# Generated deterministically by seda-macro-lef-normalizer-v1; recipe orfs-asap7-fakeram-m4-v1.
VERSION 5.8 ;
BUSBITCHARS "[]" ;
DIVIDERCHAR "/" ;

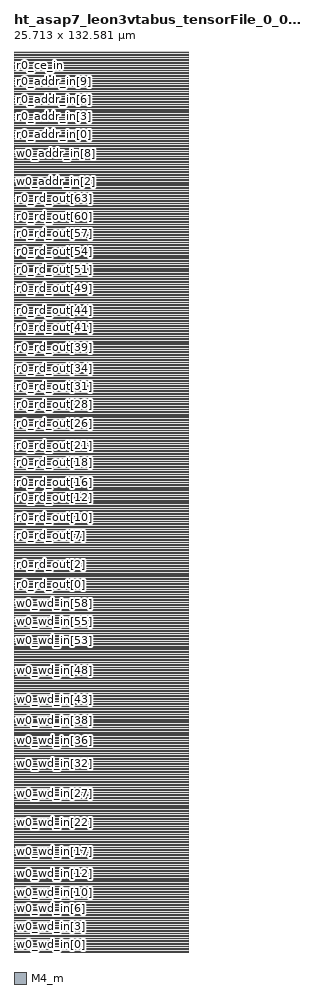
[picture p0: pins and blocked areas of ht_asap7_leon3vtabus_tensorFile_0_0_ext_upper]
MACRO ht_asap7_leon3vtabus_tensorFile_0_0_ext_upper
  FOREIGN ht_asap7_leon3vtabus_tensorFile_0_0_ext_upper 0 0 ;
  CLASS BLOCK ;
  ORIGIN 0 0 ;
  SIZE 25.713 BY 132.581 ;
  SYMMETRY X Y R90 ;
  PIN w0_wd_in[0]
    DIRECTION INPUT ;
    USE SIGNAL ;
    SHAPE ABUTMENT ;
    PORT
      LAYER M4_m ;
      RECT 0 0.048 0.024 0.072 ;
    END
  END w0_wd_in[0]
  PIN w0_wd_in[1]
    DIRECTION INPUT ;
    USE SIGNAL ;
    SHAPE ABUTMENT ;
    PORT
      LAYER M4_m ;
      RECT 0 0.912 0.024 0.936 ;
    END
  END w0_wd_in[1]
  PIN w0_wd_in[2]
    DIRECTION INPUT ;
    USE SIGNAL ;
    SHAPE ABUTMENT ;
    PORT
      LAYER M4_m ;
      RECT 0 1.776 0.024 1.8 ;
    END
  END w0_wd_in[2]
  PIN w0_wd_in[3]
    DIRECTION INPUT ;
    USE SIGNAL ;
    SHAPE ABUTMENT ;
    PORT
      LAYER M4_m ;
      RECT 0 2.64 0.024 2.664 ;
    END
  END w0_wd_in[3]
  PIN w0_wd_in[4]
    DIRECTION INPUT ;
    USE SIGNAL ;
    SHAPE ABUTMENT ;
    PORT
      LAYER M4_m ;
      RECT 0 3.504 0.024 3.528 ;
    END
  END w0_wd_in[4]
  PIN w0_wd_in[5]
    DIRECTION INPUT ;
    USE SIGNAL ;
    SHAPE ABUTMENT ;
    PORT
      LAYER M4_m ;
      RECT 0 4.368 0.024 4.392 ;
    END
  END w0_wd_in[5]
  PIN w0_wd_in[6]
    DIRECTION INPUT ;
    USE SIGNAL ;
    SHAPE ABUTMENT ;
    PORT
      LAYER M4_m ;
      RECT 0 5.232 0.024 5.256 ;
    END
  END w0_wd_in[6]
  PIN w0_wd_in[7]
    DIRECTION INPUT ;
    USE SIGNAL ;
    SHAPE ABUTMENT ;
    PORT
      LAYER M4_m ;
      RECT 0 6.096 0.024 6.12 ;
    END
  END w0_wd_in[7]
  PIN w0_wd_in[8]
    DIRECTION INPUT ;
    USE SIGNAL ;
    SHAPE ABUTMENT ;
    PORT
      LAYER M4_m ;
      RECT 0 6.96 0.024 6.984 ;
    END
  END w0_wd_in[8]
  PIN w0_wd_in[9]
    DIRECTION INPUT ;
    USE SIGNAL ;
    SHAPE ABUTMENT ;
    PORT
      LAYER M4_m ;
      RECT 0 7.824 0.024 7.848 ;
    END
  END w0_wd_in[9]
  PIN w0_wd_in[10]
    DIRECTION INPUT ;
    USE SIGNAL ;
    SHAPE ABUTMENT ;
    PORT
      LAYER M4_m ;
      RECT 0 8.688 0.024 8.712 ;
    END
  END w0_wd_in[10]
  PIN w0_wd_in[11]
    DIRECTION INPUT ;
    USE SIGNAL ;
    SHAPE ABUTMENT ;
    PORT
      LAYER M4_m ;
      RECT 0 9.552 0.024 9.576 ;
    END
  END w0_wd_in[11]
  PIN w0_wd_in[12]
    DIRECTION INPUT ;
    USE SIGNAL ;
    SHAPE ABUTMENT ;
    PORT
      LAYER M4_m ;
      RECT 0 10.416 0.024 10.44 ;
    END
  END w0_wd_in[12]
  PIN w0_wd_in[13]
    DIRECTION INPUT ;
    USE SIGNAL ;
    SHAPE ABUTMENT ;
    PORT
      LAYER M4_m ;
      RECT 0 11.28 0.024 11.304 ;
    END
  END w0_wd_in[13]
  PIN w0_wd_in[14]
    DIRECTION INPUT ;
    USE SIGNAL ;
    SHAPE ABUTMENT ;
    PORT
      LAYER M4_m ;
      RECT 0 12.144 0.024 12.168 ;
    END
  END w0_wd_in[14]
  PIN w0_wd_in[15]
    DIRECTION INPUT ;
    USE SIGNAL ;
    SHAPE ABUTMENT ;
    PORT
      LAYER M4_m ;
      RECT 0 13.008 0.024 13.032 ;
    END
  END w0_wd_in[15]
  PIN w0_wd_in[16]
    DIRECTION INPUT ;
    USE SIGNAL ;
    SHAPE ABUTMENT ;
    PORT
      LAYER M4_m ;
      RECT 0 13.872 0.024 13.896 ;
    END
  END w0_wd_in[16]
  PIN w0_wd_in[17]
    DIRECTION INPUT ;
    USE SIGNAL ;
    SHAPE ABUTMENT ;
    PORT
      LAYER M4_m ;
      RECT 0 14.736 0.024 14.76 ;
    END
  END w0_wd_in[17]
  PIN w0_wd_in[18]
    DIRECTION INPUT ;
    USE SIGNAL ;
    SHAPE ABUTMENT ;
    PORT
      LAYER M4_m ;
      RECT 0 15.6 0.024 15.624 ;
    END
  END w0_wd_in[18]
  PIN w0_wd_in[19]
    DIRECTION INPUT ;
    USE SIGNAL ;
    SHAPE ABUTMENT ;
    PORT
      LAYER M4_m ;
      RECT 0 16.464 0.024 16.488 ;
    END
  END w0_wd_in[19]
  PIN w0_wd_in[20]
    DIRECTION INPUT ;
    USE SIGNAL ;
    SHAPE ABUTMENT ;
    PORT
      LAYER M4_m ;
      RECT 0 17.328 0.024 17.352 ;
    END
  END w0_wd_in[20]
  PIN w0_wd_in[21]
    DIRECTION INPUT ;
    USE SIGNAL ;
    SHAPE ABUTMENT ;
    PORT
      LAYER M4_m ;
      RECT 0 18.192 0.024 18.216 ;
    END
  END w0_wd_in[21]
  PIN w0_wd_in[22]
    DIRECTION INPUT ;
    USE SIGNAL ;
    SHAPE ABUTMENT ;
    PORT
      LAYER M4_m ;
      RECT 0 19.056 0.024 19.08 ;
    END
  END w0_wd_in[22]
  PIN w0_wd_in[23]
    DIRECTION INPUT ;
    USE SIGNAL ;
    SHAPE ABUTMENT ;
    PORT
      LAYER M4_m ;
      RECT 0 19.92 0.024 19.944 ;
    END
  END w0_wd_in[23]
  PIN w0_wd_in[24]
    DIRECTION INPUT ;
    USE SIGNAL ;
    SHAPE ABUTMENT ;
    PORT
      LAYER M4_m ;
      RECT 0 20.784 0.024 20.808 ;
    END
  END w0_wd_in[24]
  PIN w0_wd_in[25]
    DIRECTION INPUT ;
    USE SIGNAL ;
    SHAPE ABUTMENT ;
    PORT
      LAYER M4_m ;
      RECT 0 21.648 0.024 21.672 ;
    END
  END w0_wd_in[25]
  PIN w0_wd_in[26]
    DIRECTION INPUT ;
    USE SIGNAL ;
    SHAPE ABUTMENT ;
    PORT
      LAYER M4_m ;
      RECT 0 22.512 0.024 22.536 ;
    END
  END w0_wd_in[26]
  PIN w0_wd_in[27]
    DIRECTION INPUT ;
    USE SIGNAL ;
    SHAPE ABUTMENT ;
    PORT
      LAYER M4_m ;
      RECT 0 23.376 0.024 23.4 ;
    END
  END w0_wd_in[27]
  PIN w0_wd_in[28]
    DIRECTION INPUT ;
    USE SIGNAL ;
    SHAPE ABUTMENT ;
    PORT
      LAYER M4_m ;
      RECT 0 24.24 0.024 24.264 ;
    END
  END w0_wd_in[28]
  PIN w0_wd_in[29]
    DIRECTION INPUT ;
    USE SIGNAL ;
    SHAPE ABUTMENT ;
    PORT
      LAYER M4_m ;
      RECT 0 25.104 0.024 25.128 ;
    END
  END w0_wd_in[29]
  PIN w0_wd_in[30]
    DIRECTION INPUT ;
    USE SIGNAL ;
    SHAPE ABUTMENT ;
    PORT
      LAYER M4_m ;
      RECT 0 25.968 0.024 25.992 ;
    END
  END w0_wd_in[30]
  PIN w0_wd_in[31]
    DIRECTION INPUT ;
    USE SIGNAL ;
    SHAPE ABUTMENT ;
    PORT
      LAYER M4_m ;
      RECT 0 26.832 0.024 26.856 ;
    END
  END w0_wd_in[31]
  PIN w0_wd_in[32]
    DIRECTION INPUT ;
    USE SIGNAL ;
    SHAPE ABUTMENT ;
    PORT
      LAYER M4_m ;
      RECT 0 27.696 0.024 27.72 ;
    END
  END w0_wd_in[32]
  PIN w0_wd_in[33]
    DIRECTION INPUT ;
    USE SIGNAL ;
    SHAPE ABUTMENT ;
    PORT
      LAYER M4_m ;
      RECT 0 28.56 0.024 28.584 ;
    END
  END w0_wd_in[33]
  PIN w0_wd_in[34]
    DIRECTION INPUT ;
    USE SIGNAL ;
    SHAPE ABUTMENT ;
    PORT
      LAYER M4_m ;
      RECT 0 29.424 0.024 29.448 ;
    END
  END w0_wd_in[34]
  PIN w0_wd_in[35]
    DIRECTION INPUT ;
    USE SIGNAL ;
    SHAPE ABUTMENT ;
    PORT
      LAYER M4_m ;
      RECT 0 30.288 0.024 30.312 ;
    END
  END w0_wd_in[35]
  PIN w0_wd_in[36]
    DIRECTION INPUT ;
    USE SIGNAL ;
    SHAPE ABUTMENT ;
    PORT
      LAYER M4_m ;
      RECT 0 31.152 0.024 31.176 ;
    END
  END w0_wd_in[36]
  PIN w0_wd_in[37]
    DIRECTION INPUT ;
    USE SIGNAL ;
    SHAPE ABUTMENT ;
    PORT
      LAYER M4_m ;
      RECT 0 32.016 0.024 32.04 ;
    END
  END w0_wd_in[37]
  PIN w0_wd_in[38]
    DIRECTION INPUT ;
    USE SIGNAL ;
    SHAPE ABUTMENT ;
    PORT
      LAYER M4_m ;
      RECT 0 32.88 0.024 32.904 ;
    END
  END w0_wd_in[38]
  PIN w0_wd_in[39]
    DIRECTION INPUT ;
    USE SIGNAL ;
    SHAPE ABUTMENT ;
    PORT
      LAYER M4_m ;
      RECT 0 33.744 0.024 33.768 ;
    END
  END w0_wd_in[39]
  PIN w0_wd_in[40]
    DIRECTION INPUT ;
    USE SIGNAL ;
    SHAPE ABUTMENT ;
    PORT
      LAYER M4_m ;
      RECT 0 34.608 0.024 34.632 ;
    END
  END w0_wd_in[40]
  PIN w0_wd_in[41]
    DIRECTION INPUT ;
    USE SIGNAL ;
    SHAPE ABUTMENT ;
    PORT
      LAYER M4_m ;
      RECT 0 35.472 0.024 35.496 ;
    END
  END w0_wd_in[41]
  PIN w0_wd_in[42]
    DIRECTION INPUT ;
    USE SIGNAL ;
    SHAPE ABUTMENT ;
    PORT
      LAYER M4_m ;
      RECT 0 36.336 0.024 36.36 ;
    END
  END w0_wd_in[42]
  PIN w0_wd_in[43]
    DIRECTION INPUT ;
    USE SIGNAL ;
    SHAPE ABUTMENT ;
    PORT
      LAYER M4_m ;
      RECT 0 37.2 0.024 37.224 ;
    END
  END w0_wd_in[43]
  PIN w0_wd_in[44]
    DIRECTION INPUT ;
    USE SIGNAL ;
    SHAPE ABUTMENT ;
    PORT
      LAYER M4_m ;
      RECT 0 38.064 0.024 38.088 ;
    END
  END w0_wd_in[44]
  PIN w0_wd_in[45]
    DIRECTION INPUT ;
    USE SIGNAL ;
    SHAPE ABUTMENT ;
    PORT
      LAYER M4_m ;
      RECT 0 38.928 0.024 38.952 ;
    END
  END w0_wd_in[45]
  PIN w0_wd_in[46]
    DIRECTION INPUT ;
    USE SIGNAL ;
    SHAPE ABUTMENT ;
    PORT
      LAYER M4_m ;
      RECT 0 39.792 0.024 39.816 ;
    END
  END w0_wd_in[46]
  PIN w0_wd_in[47]
    DIRECTION INPUT ;
    USE SIGNAL ;
    SHAPE ABUTMENT ;
    PORT
      LAYER M4_m ;
      RECT 0 40.656 0.024 40.68 ;
    END
  END w0_wd_in[47]
  PIN w0_wd_in[48]
    DIRECTION INPUT ;
    USE SIGNAL ;
    SHAPE ABUTMENT ;
    PORT
      LAYER M4_m ;
      RECT 0 41.52 0.024 41.544 ;
    END
  END w0_wd_in[48]
  PIN w0_wd_in[49]
    DIRECTION INPUT ;
    USE SIGNAL ;
    SHAPE ABUTMENT ;
    PORT
      LAYER M4_m ;
      RECT 0 42.384 0.024 42.408 ;
    END
  END w0_wd_in[49]
  PIN w0_wd_in[50]
    DIRECTION INPUT ;
    USE SIGNAL ;
    SHAPE ABUTMENT ;
    PORT
      LAYER M4_m ;
      RECT 0 43.248 0.024 43.272 ;
    END
  END w0_wd_in[50]
  PIN w0_wd_in[51]
    DIRECTION INPUT ;
    USE SIGNAL ;
    SHAPE ABUTMENT ;
    PORT
      LAYER M4_m ;
      RECT 0 44.112 0.024 44.136 ;
    END
  END w0_wd_in[51]
  PIN w0_wd_in[52]
    DIRECTION INPUT ;
    USE SIGNAL ;
    SHAPE ABUTMENT ;
    PORT
      LAYER M4_m ;
      RECT 0 44.976 0.024 45 ;
    END
  END w0_wd_in[52]
  PIN w0_wd_in[53]
    DIRECTION INPUT ;
    USE SIGNAL ;
    SHAPE ABUTMENT ;
    PORT
      LAYER M4_m ;
      RECT 0 45.84 0.024 45.864 ;
    END
  END w0_wd_in[53]
  PIN w0_wd_in[54]
    DIRECTION INPUT ;
    USE SIGNAL ;
    SHAPE ABUTMENT ;
    PORT
      LAYER M4_m ;
      RECT 0 46.704 0.024 46.728 ;
    END
  END w0_wd_in[54]
  PIN w0_wd_in[55]
    DIRECTION INPUT ;
    USE SIGNAL ;
    SHAPE ABUTMENT ;
    PORT
      LAYER M4_m ;
      RECT 0 47.568 0.024 47.592 ;
    END
  END w0_wd_in[55]
  PIN w0_wd_in[56]
    DIRECTION INPUT ;
    USE SIGNAL ;
    SHAPE ABUTMENT ;
    PORT
      LAYER M4_m ;
      RECT 0 48.432 0.024 48.456 ;
    END
  END w0_wd_in[56]
  PIN w0_wd_in[57]
    DIRECTION INPUT ;
    USE SIGNAL ;
    SHAPE ABUTMENT ;
    PORT
      LAYER M4_m ;
      RECT 0 49.296 0.024 49.32 ;
    END
  END w0_wd_in[57]
  PIN w0_wd_in[58]
    DIRECTION INPUT ;
    USE SIGNAL ;
    SHAPE ABUTMENT ;
    PORT
      LAYER M4_m ;
      RECT 0 50.16 0.024 50.184 ;
    END
  END w0_wd_in[58]
  PIN w0_wd_in[59]
    DIRECTION INPUT ;
    USE SIGNAL ;
    SHAPE ABUTMENT ;
    PORT
      LAYER M4_m ;
      RECT 0 51.024 0.024 51.048 ;
    END
  END w0_wd_in[59]
  PIN w0_wd_in[60]
    DIRECTION INPUT ;
    USE SIGNAL ;
    SHAPE ABUTMENT ;
    PORT
      LAYER M4_m ;
      RECT 0 51.888 0.024 51.912 ;
    END
  END w0_wd_in[60]
  PIN w0_wd_in[61]
    DIRECTION INPUT ;
    USE SIGNAL ;
    SHAPE ABUTMENT ;
    PORT
      LAYER M4_m ;
      RECT 0 52.752 0.024 52.776 ;
    END
  END w0_wd_in[61]
  PIN w0_wd_in[62]
    DIRECTION INPUT ;
    USE SIGNAL ;
    SHAPE ABUTMENT ;
    PORT
      LAYER M4_m ;
      RECT 0 53.616 0.024 53.64 ;
    END
  END w0_wd_in[62]
  PIN w0_wd_in[63]
    DIRECTION INPUT ;
    USE SIGNAL ;
    SHAPE ABUTMENT ;
    PORT
      LAYER M4_m ;
      RECT 0 54.48 0.024 54.504 ;
    END
  END w0_wd_in[63]
  PIN r0_rd_out[0]
    DIRECTION OUTPUT ;
    USE SIGNAL ;
    SHAPE ABUTMENT ;
    PORT
      LAYER M4_m ;
      RECT 0 55.344 0.024 55.368 ;
    END
  END r0_rd_out[0]
  PIN r0_rd_out[1]
    DIRECTION OUTPUT ;
    USE SIGNAL ;
    SHAPE ABUTMENT ;
    PORT
      LAYER M4_m ;
      RECT 0 56.208 0.024 56.232 ;
    END
  END r0_rd_out[1]
  PIN r0_rd_out[2]
    DIRECTION OUTPUT ;
    USE SIGNAL ;
    SHAPE ABUTMENT ;
    PORT
      LAYER M4_m ;
      RECT 0 57.072 0.024 57.096 ;
    END
  END r0_rd_out[2]
  PIN r0_rd_out[3]
    DIRECTION OUTPUT ;
    USE SIGNAL ;
    SHAPE ABUTMENT ;
    PORT
      LAYER M4_m ;
      RECT 0 57.936 0.024 57.96 ;
    END
  END r0_rd_out[3]
  PIN r0_rd_out[4]
    DIRECTION OUTPUT ;
    USE SIGNAL ;
    SHAPE ABUTMENT ;
    PORT
      LAYER M4_m ;
      RECT 0 58.8 0.024 58.824 ;
    END
  END r0_rd_out[4]
  PIN r0_rd_out[5]
    DIRECTION OUTPUT ;
    USE SIGNAL ;
    SHAPE ABUTMENT ;
    PORT
      LAYER M4_m ;
      RECT 0 59.664 0.024 59.688 ;
    END
  END r0_rd_out[5]
  PIN r0_rd_out[6]
    DIRECTION OUTPUT ;
    USE SIGNAL ;
    SHAPE ABUTMENT ;
    PORT
      LAYER M4_m ;
      RECT 0 60.528 0.024 60.552 ;
    END
  END r0_rd_out[6]
  PIN r0_rd_out[7]
    DIRECTION OUTPUT ;
    USE SIGNAL ;
    SHAPE ABUTMENT ;
    PORT
      LAYER M4_m ;
      RECT 0 61.392 0.024 61.416 ;
    END
  END r0_rd_out[7]
  PIN r0_rd_out[8]
    DIRECTION OUTPUT ;
    USE SIGNAL ;
    SHAPE ABUTMENT ;
    PORT
      LAYER M4_m ;
      RECT 0 62.256 0.024 62.28 ;
    END
  END r0_rd_out[8]
  PIN r0_rd_out[9]
    DIRECTION OUTPUT ;
    USE SIGNAL ;
    SHAPE ABUTMENT ;
    PORT
      LAYER M4_m ;
      RECT 0 63.12 0.024 63.144 ;
    END
  END r0_rd_out[9]
  PIN r0_rd_out[10]
    DIRECTION OUTPUT ;
    USE SIGNAL ;
    SHAPE ABUTMENT ;
    PORT
      LAYER M4_m ;
      RECT 0 63.984 0.024 64.008 ;
    END
  END r0_rd_out[10]
  PIN r0_rd_out[11]
    DIRECTION OUTPUT ;
    USE SIGNAL ;
    SHAPE ABUTMENT ;
    PORT
      LAYER M4_m ;
      RECT 0 64.848 0.024 64.872 ;
    END
  END r0_rd_out[11]
  PIN r0_rd_out[12]
    DIRECTION OUTPUT ;
    USE SIGNAL ;
    SHAPE ABUTMENT ;
    PORT
      LAYER M4_m ;
      RECT 0 65.712 0.024 65.736 ;
    END
  END r0_rd_out[12]
  PIN r0_rd_out[13]
    DIRECTION OUTPUT ;
    USE SIGNAL ;
    SHAPE ABUTMENT ;
    PORT
      LAYER M4_m ;
      RECT 0 66.576 0.024 66.6 ;
    END
  END r0_rd_out[13]
  PIN r0_rd_out[14]
    DIRECTION OUTPUT ;
    USE SIGNAL ;
    SHAPE ABUTMENT ;
    PORT
      LAYER M4_m ;
      RECT 0 67.44 0.024 67.464 ;
    END
  END r0_rd_out[14]
  PIN r0_rd_out[15]
    DIRECTION OUTPUT ;
    USE SIGNAL ;
    SHAPE ABUTMENT ;
    PORT
      LAYER M4_m ;
      RECT 0 68.304 0.024 68.328 ;
    END
  END r0_rd_out[15]
  PIN r0_rd_out[16]
    DIRECTION OUTPUT ;
    USE SIGNAL ;
    SHAPE ABUTMENT ;
    PORT
      LAYER M4_m ;
      RECT 0 69.168 0.024 69.192 ;
    END
  END r0_rd_out[16]
  PIN r0_rd_out[17]
    DIRECTION OUTPUT ;
    USE SIGNAL ;
    SHAPE ABUTMENT ;
    PORT
      LAYER M4_m ;
      RECT 0 70.032 0.024 70.056 ;
    END
  END r0_rd_out[17]
  PIN r0_rd_out[18]
    DIRECTION OUTPUT ;
    USE SIGNAL ;
    SHAPE ABUTMENT ;
    PORT
      LAYER M4_m ;
      RECT 0 70.896 0.024 70.92 ;
    END
  END r0_rd_out[18]
  PIN r0_rd_out[19]
    DIRECTION OUTPUT ;
    USE SIGNAL ;
    SHAPE ABUTMENT ;
    PORT
      LAYER M4_m ;
      RECT 0 71.76 0.024 71.784 ;
    END
  END r0_rd_out[19]
  PIN r0_rd_out[20]
    DIRECTION OUTPUT ;
    USE SIGNAL ;
    SHAPE ABUTMENT ;
    PORT
      LAYER M4_m ;
      RECT 0 72.624 0.024 72.648 ;
    END
  END r0_rd_out[20]
  PIN r0_rd_out[21]
    DIRECTION OUTPUT ;
    USE SIGNAL ;
    SHAPE ABUTMENT ;
    PORT
      LAYER M4_m ;
      RECT 0 73.488 0.024 73.512 ;
    END
  END r0_rd_out[21]
  PIN r0_rd_out[22]
    DIRECTION OUTPUT ;
    USE SIGNAL ;
    SHAPE ABUTMENT ;
    PORT
      LAYER M4_m ;
      RECT 0 74.352 0.024 74.376 ;
    END
  END r0_rd_out[22]
  PIN r0_rd_out[23]
    DIRECTION OUTPUT ;
    USE SIGNAL ;
    SHAPE ABUTMENT ;
    PORT
      LAYER M4_m ;
      RECT 0 75.216 0.024 75.24 ;
    END
  END r0_rd_out[23]
  PIN r0_rd_out[24]
    DIRECTION OUTPUT ;
    USE SIGNAL ;
    SHAPE ABUTMENT ;
    PORT
      LAYER M4_m ;
      RECT 0 76.08 0.024 76.104 ;
    END
  END r0_rd_out[24]
  PIN r0_rd_out[25]
    DIRECTION OUTPUT ;
    USE SIGNAL ;
    SHAPE ABUTMENT ;
    PORT
      LAYER M4_m ;
      RECT 0 76.944 0.024 76.968 ;
    END
  END r0_rd_out[25]
  PIN r0_rd_out[26]
    DIRECTION OUTPUT ;
    USE SIGNAL ;
    SHAPE ABUTMENT ;
    PORT
      LAYER M4_m ;
      RECT 0 77.808 0.024 77.832 ;
    END
  END r0_rd_out[26]
  PIN r0_rd_out[27]
    DIRECTION OUTPUT ;
    USE SIGNAL ;
    SHAPE ABUTMENT ;
    PORT
      LAYER M4_m ;
      RECT 0 78.672 0.024 78.696 ;
    END
  END r0_rd_out[27]
  PIN r0_rd_out[28]
    DIRECTION OUTPUT ;
    USE SIGNAL ;
    SHAPE ABUTMENT ;
    PORT
      LAYER M4_m ;
      RECT 0 79.536 0.024 79.56 ;
    END
  END r0_rd_out[28]
  PIN r0_rd_out[29]
    DIRECTION OUTPUT ;
    USE SIGNAL ;
    SHAPE ABUTMENT ;
    PORT
      LAYER M4_m ;
      RECT 0 80.4 0.024 80.424 ;
    END
  END r0_rd_out[29]
  PIN r0_rd_out[30]
    DIRECTION OUTPUT ;
    USE SIGNAL ;
    SHAPE ABUTMENT ;
    PORT
      LAYER M4_m ;
      RECT 0 81.264 0.024 81.288 ;
    END
  END r0_rd_out[30]
  PIN r0_rd_out[31]
    DIRECTION OUTPUT ;
    USE SIGNAL ;
    SHAPE ABUTMENT ;
    PORT
      LAYER M4_m ;
      RECT 0 82.128 0.024 82.152 ;
    END
  END r0_rd_out[31]
  PIN r0_rd_out[32]
    DIRECTION OUTPUT ;
    USE SIGNAL ;
    SHAPE ABUTMENT ;
    PORT
      LAYER M4_m ;
      RECT 0 82.992 0.024 83.016 ;
    END
  END r0_rd_out[32]
  PIN r0_rd_out[33]
    DIRECTION OUTPUT ;
    USE SIGNAL ;
    SHAPE ABUTMENT ;
    PORT
      LAYER M4_m ;
      RECT 0 83.856 0.024 83.88 ;
    END
  END r0_rd_out[33]
  PIN r0_rd_out[34]
    DIRECTION OUTPUT ;
    USE SIGNAL ;
    SHAPE ABUTMENT ;
    PORT
      LAYER M4_m ;
      RECT 0 84.72 0.024 84.744 ;
    END
  END r0_rd_out[34]
  PIN r0_rd_out[35]
    DIRECTION OUTPUT ;
    USE SIGNAL ;
    SHAPE ABUTMENT ;
    PORT
      LAYER M4_m ;
      RECT 0 85.584 0.024 85.608 ;
    END
  END r0_rd_out[35]
  PIN r0_rd_out[36]
    DIRECTION OUTPUT ;
    USE SIGNAL ;
    SHAPE ABUTMENT ;
    PORT
      LAYER M4_m ;
      RECT 0 86.448 0.024 86.472 ;
    END
  END r0_rd_out[36]
  PIN r0_rd_out[37]
    DIRECTION OUTPUT ;
    USE SIGNAL ;
    SHAPE ABUTMENT ;
    PORT
      LAYER M4_m ;
      RECT 0 87.312 0.024 87.336 ;
    END
  END r0_rd_out[37]
  PIN r0_rd_out[38]
    DIRECTION OUTPUT ;
    USE SIGNAL ;
    SHAPE ABUTMENT ;
    PORT
      LAYER M4_m ;
      RECT 0 88.176 0.024 88.2 ;
    END
  END r0_rd_out[38]
  PIN r0_rd_out[39]
    DIRECTION OUTPUT ;
    USE SIGNAL ;
    SHAPE ABUTMENT ;
    PORT
      LAYER M4_m ;
      RECT 0 89.04 0.024 89.064 ;
    END
  END r0_rd_out[39]
  PIN r0_rd_out[40]
    DIRECTION OUTPUT ;
    USE SIGNAL ;
    SHAPE ABUTMENT ;
    PORT
      LAYER M4_m ;
      RECT 0 89.904 0.024 89.928 ;
    END
  END r0_rd_out[40]
  PIN r0_rd_out[41]
    DIRECTION OUTPUT ;
    USE SIGNAL ;
    SHAPE ABUTMENT ;
    PORT
      LAYER M4_m ;
      RECT 0 90.768 0.024 90.792 ;
    END
  END r0_rd_out[41]
  PIN r0_rd_out[42]
    DIRECTION OUTPUT ;
    USE SIGNAL ;
    SHAPE ABUTMENT ;
    PORT
      LAYER M4_m ;
      RECT 0 91.632 0.024 91.656 ;
    END
  END r0_rd_out[42]
  PIN r0_rd_out[43]
    DIRECTION OUTPUT ;
    USE SIGNAL ;
    SHAPE ABUTMENT ;
    PORT
      LAYER M4_m ;
      RECT 0 92.496 0.024 92.52 ;
    END
  END r0_rd_out[43]
  PIN r0_rd_out[44]
    DIRECTION OUTPUT ;
    USE SIGNAL ;
    SHAPE ABUTMENT ;
    PORT
      LAYER M4_m ;
      RECT 0 93.36 0.024 93.384 ;
    END
  END r0_rd_out[44]
  PIN r0_rd_out[45]
    DIRECTION OUTPUT ;
    USE SIGNAL ;
    SHAPE ABUTMENT ;
    PORT
      LAYER M4_m ;
      RECT 0 94.224 0.024 94.248 ;
    END
  END r0_rd_out[45]
  PIN r0_rd_out[46]
    DIRECTION OUTPUT ;
    USE SIGNAL ;
    SHAPE ABUTMENT ;
    PORT
      LAYER M4_m ;
      RECT 0 95.088 0.024 95.112 ;
    END
  END r0_rd_out[46]
  PIN r0_rd_out[47]
    DIRECTION OUTPUT ;
    USE SIGNAL ;
    SHAPE ABUTMENT ;
    PORT
      LAYER M4_m ;
      RECT 0 95.952 0.024 95.976 ;
    END
  END r0_rd_out[47]
  PIN r0_rd_out[48]
    DIRECTION OUTPUT ;
    USE SIGNAL ;
    SHAPE ABUTMENT ;
    PORT
      LAYER M4_m ;
      RECT 0 96.816 0.024 96.84 ;
    END
  END r0_rd_out[48]
  PIN r0_rd_out[49]
    DIRECTION OUTPUT ;
    USE SIGNAL ;
    SHAPE ABUTMENT ;
    PORT
      LAYER M4_m ;
      RECT 0 97.68 0.024 97.704 ;
    END
  END r0_rd_out[49]
  PIN r0_rd_out[50]
    DIRECTION OUTPUT ;
    USE SIGNAL ;
    SHAPE ABUTMENT ;
    PORT
      LAYER M4_m ;
      RECT 0 98.544 0.024 98.568 ;
    END
  END r0_rd_out[50]
  PIN r0_rd_out[51]
    DIRECTION OUTPUT ;
    USE SIGNAL ;
    SHAPE ABUTMENT ;
    PORT
      LAYER M4_m ;
      RECT 0 99.408 0.024 99.432 ;
    END
  END r0_rd_out[51]
  PIN r0_rd_out[52]
    DIRECTION OUTPUT ;
    USE SIGNAL ;
    SHAPE ABUTMENT ;
    PORT
      LAYER M4_m ;
      RECT 0 100.272 0.024 100.296 ;
    END
  END r0_rd_out[52]
  PIN r0_rd_out[53]
    DIRECTION OUTPUT ;
    USE SIGNAL ;
    SHAPE ABUTMENT ;
    PORT
      LAYER M4_m ;
      RECT 0 101.136 0.024 101.16 ;
    END
  END r0_rd_out[53]
  PIN r0_rd_out[54]
    DIRECTION OUTPUT ;
    USE SIGNAL ;
    SHAPE ABUTMENT ;
    PORT
      LAYER M4_m ;
      RECT 0 102 0.024 102.024 ;
    END
  END r0_rd_out[54]
  PIN r0_rd_out[55]
    DIRECTION OUTPUT ;
    USE SIGNAL ;
    SHAPE ABUTMENT ;
    PORT
      LAYER M4_m ;
      RECT 0 102.864 0.024 102.888 ;
    END
  END r0_rd_out[55]
  PIN r0_rd_out[56]
    DIRECTION OUTPUT ;
    USE SIGNAL ;
    SHAPE ABUTMENT ;
    PORT
      LAYER M4_m ;
      RECT 0 103.728 0.024 103.752 ;
    END
  END r0_rd_out[56]
  PIN r0_rd_out[57]
    DIRECTION OUTPUT ;
    USE SIGNAL ;
    SHAPE ABUTMENT ;
    PORT
      LAYER M4_m ;
      RECT 0 104.592 0.024 104.616 ;
    END
  END r0_rd_out[57]
  PIN r0_rd_out[58]
    DIRECTION OUTPUT ;
    USE SIGNAL ;
    SHAPE ABUTMENT ;
    PORT
      LAYER M4_m ;
      RECT 0 105.456 0.024 105.48 ;
    END
  END r0_rd_out[58]
  PIN r0_rd_out[59]
    DIRECTION OUTPUT ;
    USE SIGNAL ;
    SHAPE ABUTMENT ;
    PORT
      LAYER M4_m ;
      RECT 0 106.32 0.024 106.344 ;
    END
  END r0_rd_out[59]
  PIN r0_rd_out[60]
    DIRECTION OUTPUT ;
    USE SIGNAL ;
    SHAPE ABUTMENT ;
    PORT
      LAYER M4_m ;
      RECT 0 107.184 0.024 107.208 ;
    END
  END r0_rd_out[60]
  PIN r0_rd_out[61]
    DIRECTION OUTPUT ;
    USE SIGNAL ;
    SHAPE ABUTMENT ;
    PORT
      LAYER M4_m ;
      RECT 0 108.048 0.024 108.072 ;
    END
  END r0_rd_out[61]
  PIN r0_rd_out[62]
    DIRECTION OUTPUT ;
    USE SIGNAL ;
    SHAPE ABUTMENT ;
    PORT
      LAYER M4_m ;
      RECT 0 108.912 0.024 108.936 ;
    END
  END r0_rd_out[62]
  PIN r0_rd_out[63]
    DIRECTION OUTPUT ;
    USE SIGNAL ;
    SHAPE ABUTMENT ;
    PORT
      LAYER M4_m ;
      RECT 0 109.776 0.024 109.8 ;
    END
  END r0_rd_out[63]
  PIN w0_addr_in[0]
    DIRECTION INPUT ;
    USE SIGNAL ;
    SHAPE ABUTMENT ;
    PORT
      LAYER M4_m ;
      RECT 0 110.64 0.024 110.664 ;
    END
  END w0_addr_in[0]
  PIN w0_addr_in[1]
    DIRECTION INPUT ;
    USE SIGNAL ;
    SHAPE ABUTMENT ;
    PORT
      LAYER M4_m ;
      RECT 0 111.504 0.024 111.528 ;
    END
  END w0_addr_in[1]
  PIN w0_addr_in[2]
    DIRECTION INPUT ;
    USE SIGNAL ;
    SHAPE ABUTMENT ;
    PORT
      LAYER M4_m ;
      RECT 0 112.368 0.024 112.392 ;
    END
  END w0_addr_in[2]
  PIN w0_addr_in[3]
    DIRECTION INPUT ;
    USE SIGNAL ;
    SHAPE ABUTMENT ;
    PORT
      LAYER M4_m ;
      RECT 0 113.232 0.024 113.256 ;
    END
  END w0_addr_in[3]
  PIN w0_addr_in[4]
    DIRECTION INPUT ;
    USE SIGNAL ;
    SHAPE ABUTMENT ;
    PORT
      LAYER M4_m ;
      RECT 0 114.096 0.024 114.12 ;
    END
  END w0_addr_in[4]
  PIN w0_addr_in[5]
    DIRECTION INPUT ;
    USE SIGNAL ;
    SHAPE ABUTMENT ;
    PORT
      LAYER M4_m ;
      RECT 0 114.96 0.024 114.984 ;
    END
  END w0_addr_in[5]
  PIN w0_addr_in[6]
    DIRECTION INPUT ;
    USE SIGNAL ;
    SHAPE ABUTMENT ;
    PORT
      LAYER M4_m ;
      RECT 0 115.824 0.024 115.848 ;
    END
  END w0_addr_in[6]
  PIN w0_addr_in[7]
    DIRECTION INPUT ;
    USE SIGNAL ;
    SHAPE ABUTMENT ;
    PORT
      LAYER M4_m ;
      RECT 0 116.688 0.024 116.712 ;
    END
  END w0_addr_in[7]
  PIN w0_addr_in[8]
    DIRECTION INPUT ;
    USE SIGNAL ;
    SHAPE ABUTMENT ;
    PORT
      LAYER M4_m ;
      RECT 0 117.552 0.024 117.576 ;
    END
  END w0_addr_in[8]
  PIN w0_addr_in[9]
    DIRECTION INPUT ;
    USE SIGNAL ;
    SHAPE ABUTMENT ;
    PORT
      LAYER M4_m ;
      RECT 0 118.416 0.024 118.44 ;
    END
  END w0_addr_in[9]
  PIN r0_addr_in[0]
    DIRECTION INPUT ;
    USE SIGNAL ;
    SHAPE ABUTMENT ;
    PORT
      LAYER M4_m ;
      RECT 0 119.28 0.024 119.304 ;
    END
  END r0_addr_in[0]
  PIN r0_addr_in[1]
    DIRECTION INPUT ;
    USE SIGNAL ;
    SHAPE ABUTMENT ;
    PORT
      LAYER M4_m ;
      RECT 0 120.144 0.024 120.168 ;
    END
  END r0_addr_in[1]
  PIN r0_addr_in[2]
    DIRECTION INPUT ;
    USE SIGNAL ;
    SHAPE ABUTMENT ;
    PORT
      LAYER M4_m ;
      RECT 0 121.008 0.024 121.032 ;
    END
  END r0_addr_in[2]
  PIN r0_addr_in[3]
    DIRECTION INPUT ;
    USE SIGNAL ;
    SHAPE ABUTMENT ;
    PORT
      LAYER M4_m ;
      RECT 0 121.872 0.024 121.896 ;
    END
  END r0_addr_in[3]
  PIN r0_addr_in[4]
    DIRECTION INPUT ;
    USE SIGNAL ;
    SHAPE ABUTMENT ;
    PORT
      LAYER M4_m ;
      RECT 0 122.736 0.024 122.76 ;
    END
  END r0_addr_in[4]
  PIN r0_addr_in[5]
    DIRECTION INPUT ;
    USE SIGNAL ;
    SHAPE ABUTMENT ;
    PORT
      LAYER M4_m ;
      RECT 0 123.6 0.024 123.624 ;
    END
  END r0_addr_in[5]
  PIN r0_addr_in[6]
    DIRECTION INPUT ;
    USE SIGNAL ;
    SHAPE ABUTMENT ;
    PORT
      LAYER M4_m ;
      RECT 0 124.464 0.024 124.488 ;
    END
  END r0_addr_in[6]
  PIN r0_addr_in[7]
    DIRECTION INPUT ;
    USE SIGNAL ;
    SHAPE ABUTMENT ;
    PORT
      LAYER M4_m ;
      RECT 0 125.328 0.024 125.352 ;
    END
  END r0_addr_in[7]
  PIN r0_addr_in[8]
    DIRECTION INPUT ;
    USE SIGNAL ;
    SHAPE ABUTMENT ;
    PORT
      LAYER M4_m ;
      RECT 0 126.192 0.024 126.216 ;
    END
  END r0_addr_in[8]
  PIN r0_addr_in[9]
    DIRECTION INPUT ;
    USE SIGNAL ;
    SHAPE ABUTMENT ;
    PORT
      LAYER M4_m ;
      RECT 0 127.056 0.024 127.08 ;
    END
  END r0_addr_in[9]
  PIN w0_we_in
    DIRECTION INPUT ;
    USE SIGNAL ;
    SHAPE ABUTMENT ;
    PORT
      LAYER M4_m ;
      RECT 0 127.92 0.024 127.944 ;
    END
  END w0_we_in
  PIN w0_ce_in
    DIRECTION INPUT ;
    USE SIGNAL ;
    SHAPE ABUTMENT ;
    PORT
      LAYER M4_m ;
      RECT 0 128.784 0.024 128.808 ;
    END
  END w0_ce_in
  PIN w0_clk
    DIRECTION INPUT ;
    USE SIGNAL ;
    SHAPE ABUTMENT ;
    PORT
      LAYER M4_m ;
      RECT 0 129.648 0.024 129.672 ;
    END
  END w0_clk
  PIN r0_ce_in
    DIRECTION INPUT ;
    USE SIGNAL ;
    SHAPE ABUTMENT ;
    PORT
      LAYER M4_m ;
      RECT 0 130.512 0.024 130.536 ;
    END
  END r0_ce_in
  PIN r0_clk
    DIRECTION INPUT ;
    USE SIGNAL ;
    SHAPE ABUTMENT ;
    PORT
      LAYER M4_m ;
      RECT 0 131.376 0.024 131.4 ;
    END
  END r0_clk
  PIN VSS
    DIRECTION INOUT ;
    USE GROUND ;
    PORT
      LAYER M4_m ;
      RECT 0.048 0 25.665 0.096 ;
      RECT 0.048 0.768 25.665 0.864 ;
      RECT 0.048 1.536 25.665 1.632 ;
      RECT 0.048 2.304 25.665 2.4 ;
      RECT 0.048 3.072 25.665 3.168 ;
      RECT 0.048 3.84 25.665 3.936 ;
      RECT 0.048 4.608 25.665 4.704 ;
      RECT 0.048 5.376 25.665 5.472 ;
      RECT 0.048 6.144 25.665 6.24 ;
      RECT 0.048 6.912 25.665 7.008 ;
      RECT 0.048 7.68 25.665 7.776 ;
      RECT 0.048 8.448 25.665 8.544 ;
      RECT 0.048 9.216 25.665 9.312 ;
      RECT 0.048 9.984 25.665 10.08 ;
      RECT 0.048 10.752 25.665 10.848 ;
      RECT 0.048 11.52 25.665 11.616 ;
      RECT 0.048 12.288 25.665 12.384 ;
      RECT 0.048 13.056 25.665 13.152 ;
      RECT 0.048 13.824 25.665 13.92 ;
      RECT 0.048 14.592 25.665 14.688 ;
      RECT 0.048 15.36 25.665 15.456 ;
      RECT 0.048 16.128 25.665 16.224 ;
      RECT 0.048 16.896 25.665 16.992 ;
      RECT 0.048 17.664 25.665 17.76 ;
      RECT 0.048 18.432 25.665 18.528 ;
      RECT 0.048 19.2 25.665 19.296 ;
      RECT 0.048 19.968 25.665 20.064 ;
      RECT 0.048 20.736 25.665 20.832 ;
      RECT 0.048 21.504 25.665 21.6 ;
      RECT 0.048 22.272 25.665 22.368 ;
      RECT 0.048 23.04 25.665 23.136 ;
      RECT 0.048 23.808 25.665 23.904 ;
      RECT 0.048 24.576 25.665 24.672 ;
      RECT 0.048 25.344 25.665 25.44 ;
      RECT 0.048 26.112 25.665 26.208 ;
      RECT 0.048 26.88 25.665 26.976 ;
      RECT 0.048 27.648 25.665 27.744 ;
      RECT 0.048 28.416 25.665 28.512 ;
      RECT 0.048 29.184 25.665 29.28 ;
      RECT 0.048 29.952 25.665 30.048 ;
      RECT 0.048 30.72 25.665 30.816 ;
      RECT 0.048 31.488 25.665 31.584 ;
      RECT 0.048 32.256 25.665 32.352 ;
      RECT 0.048 33.024 25.665 33.12 ;
      RECT 0.048 33.792 25.665 33.888 ;
      RECT 0.048 34.56 25.665 34.656 ;
      RECT 0.048 35.328 25.665 35.424 ;
      RECT 0.048 36.096 25.665 36.192 ;
      RECT 0.048 36.864 25.665 36.96 ;
      RECT 0.048 37.632 25.665 37.728 ;
      RECT 0.048 38.4 25.665 38.496 ;
      RECT 0.048 39.168 25.665 39.264 ;
      RECT 0.048 39.936 25.665 40.032 ;
      RECT 0.048 40.704 25.665 40.8 ;
      RECT 0.048 41.472 25.665 41.568 ;
      RECT 0.048 42.24 25.665 42.336 ;
      RECT 0.048 43.008 25.665 43.104 ;
      RECT 0.048 43.776 25.665 43.872 ;
      RECT 0.048 44.544 25.665 44.64 ;
      RECT 0.048 45.312 25.665 45.408 ;
      RECT 0.048 46.08 25.665 46.176 ;
      RECT 0.048 46.848 25.665 46.944 ;
      RECT 0.048 47.616 25.665 47.712 ;
      RECT 0.048 48.384 25.665 48.48 ;
      RECT 0.048 49.152 25.665 49.248 ;
      RECT 0.048 49.92 25.665 50.016 ;
      RECT 0.048 50.688 25.665 50.784 ;
      RECT 0.048 51.456 25.665 51.552 ;
      RECT 0.048 52.224 25.665 52.32 ;
      RECT 0.048 52.992 25.665 53.088 ;
      RECT 0.048 53.76 25.665 53.856 ;
      RECT 0.048 54.528 25.665 54.624 ;
      RECT 0.048 55.296 25.665 55.392 ;
      RECT 0.048 56.064 25.665 56.16 ;
      RECT 0.048 56.832 25.665 56.928 ;
      RECT 0.048 57.6 25.665 57.696 ;
      RECT 0.048 58.368 25.665 58.464 ;
      RECT 0.048 59.136 25.665 59.232 ;
      RECT 0.048 59.904 25.665 60 ;
      RECT 0.048 60.672 25.665 60.768 ;
      RECT 0.048 61.44 25.665 61.536 ;
      RECT 0.048 62.208 25.665 62.304 ;
      RECT 0.048 62.976 25.665 63.072 ;
      RECT 0.048 63.744 25.665 63.84 ;
      RECT 0.048 64.512 25.665 64.608 ;
      RECT 0.048 65.28 25.665 65.376 ;
      RECT 0.048 66.048 25.665 66.144 ;
      RECT 0.048 66.816 25.665 66.912 ;
      RECT 0.048 67.584 25.665 67.68 ;
      RECT 0.048 68.352 25.665 68.448 ;
      RECT 0.048 69.12 25.665 69.216 ;
      RECT 0.048 69.888 25.665 69.984 ;
      RECT 0.048 70.656 25.665 70.752 ;
      RECT 0.048 71.424 25.665 71.52 ;
      RECT 0.048 72.192 25.665 72.288 ;
      RECT 0.048 72.96 25.665 73.056 ;
      RECT 0.048 73.728 25.665 73.824 ;
      RECT 0.048 74.496 25.665 74.592 ;
      RECT 0.048 75.264 25.665 75.36 ;
      RECT 0.048 76.032 25.665 76.128 ;
      RECT 0.048 76.8 25.665 76.896 ;
      RECT 0.048 77.568 25.665 77.664 ;
      RECT 0.048 78.336 25.665 78.432 ;
      RECT 0.048 79.104 25.665 79.2 ;
      RECT 0.048 79.872 25.665 79.968 ;
      RECT 0.048 80.64 25.665 80.736 ;
      RECT 0.048 81.408 25.665 81.504 ;
      RECT 0.048 82.176 25.665 82.272 ;
      RECT 0.048 82.944 25.665 83.04 ;
      RECT 0.048 83.712 25.665 83.808 ;
      RECT 0.048 84.48 25.665 84.576 ;
      RECT 0.048 85.248 25.665 85.344 ;
      RECT 0.048 86.016 25.665 86.112 ;
      RECT 0.048 86.784 25.665 86.88 ;
      RECT 0.048 87.552 25.665 87.648 ;
      RECT 0.048 88.32 25.665 88.416 ;
      RECT 0.048 89.088 25.665 89.184 ;
      RECT 0.048 89.856 25.665 89.952 ;
      RECT 0.048 90.624 25.665 90.72 ;
      RECT 0.048 91.392 25.665 91.488 ;
      RECT 0.048 92.16 25.665 92.256 ;
      RECT 0.048 92.928 25.665 93.024 ;
      RECT 0.048 93.696 25.665 93.792 ;
      RECT 0.048 94.464 25.665 94.56 ;
      RECT 0.048 95.232 25.665 95.328 ;
      RECT 0.048 96 25.665 96.096 ;
      RECT 0.048 96.768 25.665 96.864 ;
      RECT 0.048 97.536 25.665 97.632 ;
      RECT 0.048 98.304 25.665 98.4 ;
      RECT 0.048 99.072 25.665 99.168 ;
      RECT 0.048 99.84 25.665 99.936 ;
      RECT 0.048 100.608 25.665 100.704 ;
      RECT 0.048 101.376 25.665 101.472 ;
      RECT 0.048 102.144 25.665 102.24 ;
      RECT 0.048 102.912 25.665 103.008 ;
      RECT 0.048 103.68 25.665 103.776 ;
      RECT 0.048 104.448 25.665 104.544 ;
      RECT 0.048 105.216 25.665 105.312 ;
      RECT 0.048 105.984 25.665 106.08 ;
      RECT 0.048 106.752 25.665 106.848 ;
      RECT 0.048 107.52 25.665 107.616 ;
      RECT 0.048 108.288 25.665 108.384 ;
      RECT 0.048 109.056 25.665 109.152 ;
      RECT 0.048 109.824 25.665 109.92 ;
      RECT 0.048 110.592 25.665 110.688 ;
      RECT 0.048 111.36 25.665 111.456 ;
      RECT 0.048 112.128 25.665 112.224 ;
      RECT 0.048 112.896 25.665 112.992 ;
      RECT 0.048 113.664 25.665 113.76 ;
      RECT 0.048 114.432 25.665 114.528 ;
      RECT 0.048 115.2 25.665 115.296 ;
      RECT 0.048 115.968 25.665 116.064 ;
      RECT 0.048 116.736 25.665 116.832 ;
      RECT 0.048 117.504 25.665 117.6 ;
      RECT 0.048 118.272 25.665 118.368 ;
      RECT 0.048 119.04 25.665 119.136 ;
      RECT 0.048 119.808 25.665 119.904 ;
      RECT 0.048 120.576 25.665 120.672 ;
      RECT 0.048 121.344 25.665 121.44 ;
      RECT 0.048 122.112 25.665 122.208 ;
      RECT 0.048 122.88 25.665 122.976 ;
      RECT 0.048 123.648 25.665 123.744 ;
      RECT 0.048 124.416 25.665 124.512 ;
      RECT 0.048 125.184 25.665 125.28 ;
      RECT 0.048 125.952 25.665 126.048 ;
      RECT 0.048 126.72 25.665 126.816 ;
      RECT 0.048 127.488 25.665 127.584 ;
      RECT 0.048 128.256 25.665 128.352 ;
      RECT 0.048 129.024 25.665 129.12 ;
      RECT 0.048 129.792 25.665 129.888 ;
      RECT 0.048 130.56 25.665 130.656 ;
      RECT 0.048 131.328 25.665 131.424 ;
      RECT 0.048 132.096 25.665 132.192 ;
    END
  END VSS
  PIN VDD
    DIRECTION INOUT ;
    USE POWER ;
    PORT
      LAYER M4_m ;
      RECT 0.048 0.384 25.665 0.48 ;
      RECT 0.048 1.152 25.665 1.248 ;
      RECT 0.048 1.92 25.665 2.016 ;
      RECT 0.048 2.688 25.665 2.784 ;
      RECT 0.048 3.456 25.665 3.552 ;
      RECT 0.048 4.224 25.665 4.32 ;
      RECT 0.048 4.992 25.665 5.088 ;
      RECT 0.048 5.76 25.665 5.856 ;
      RECT 0.048 6.528 25.665 6.624 ;
      RECT 0.048 7.296 25.665 7.392 ;
      RECT 0.048 8.064 25.665 8.16 ;
      RECT 0.048 8.832 25.665 8.928 ;
      RECT 0.048 9.6 25.665 9.696 ;
      RECT 0.048 10.368 25.665 10.464 ;
      RECT 0.048 11.136 25.665 11.232 ;
      RECT 0.048 11.904 25.665 12 ;
      RECT 0.048 12.672 25.665 12.768 ;
      RECT 0.048 13.44 25.665 13.536 ;
      RECT 0.048 14.208 25.665 14.304 ;
      RECT 0.048 14.976 25.665 15.072 ;
      RECT 0.048 15.744 25.665 15.84 ;
      RECT 0.048 16.512 25.665 16.608 ;
      RECT 0.048 17.28 25.665 17.376 ;
      RECT 0.048 18.048 25.665 18.144 ;
      RECT 0.048 18.816 25.665 18.912 ;
      RECT 0.048 19.584 25.665 19.68 ;
      RECT 0.048 20.352 25.665 20.448 ;
      RECT 0.048 21.12 25.665 21.216 ;
      RECT 0.048 21.888 25.665 21.984 ;
      RECT 0.048 22.656 25.665 22.752 ;
      RECT 0.048 23.424 25.665 23.52 ;
      RECT 0.048 24.192 25.665 24.288 ;
      RECT 0.048 24.96 25.665 25.056 ;
      RECT 0.048 25.728 25.665 25.824 ;
      RECT 0.048 26.496 25.665 26.592 ;
      RECT 0.048 27.264 25.665 27.36 ;
      RECT 0.048 28.032 25.665 28.128 ;
      RECT 0.048 28.8 25.665 28.896 ;
      RECT 0.048 29.568 25.665 29.664 ;
      RECT 0.048 30.336 25.665 30.432 ;
      RECT 0.048 31.104 25.665 31.2 ;
      RECT 0.048 31.872 25.665 31.968 ;
      RECT 0.048 32.64 25.665 32.736 ;
      RECT 0.048 33.408 25.665 33.504 ;
      RECT 0.048 34.176 25.665 34.272 ;
      RECT 0.048 34.944 25.665 35.04 ;
      RECT 0.048 35.712 25.665 35.808 ;
      RECT 0.048 36.48 25.665 36.576 ;
      RECT 0.048 37.248 25.665 37.344 ;
      RECT 0.048 38.016 25.665 38.112 ;
      RECT 0.048 38.784 25.665 38.88 ;
      RECT 0.048 39.552 25.665 39.648 ;
      RECT 0.048 40.32 25.665 40.416 ;
      RECT 0.048 41.088 25.665 41.184 ;
      RECT 0.048 41.856 25.665 41.952 ;
      RECT 0.048 42.624 25.665 42.72 ;
      RECT 0.048 43.392 25.665 43.488 ;
      RECT 0.048 44.16 25.665 44.256 ;
      RECT 0.048 44.928 25.665 45.024 ;
      RECT 0.048 45.696 25.665 45.792 ;
      RECT 0.048 46.464 25.665 46.56 ;
      RECT 0.048 47.232 25.665 47.328 ;
      RECT 0.048 48 25.665 48.096 ;
      RECT 0.048 48.768 25.665 48.864 ;
      RECT 0.048 49.536 25.665 49.632 ;
      RECT 0.048 50.304 25.665 50.4 ;
      RECT 0.048 51.072 25.665 51.168 ;
      RECT 0.048 51.84 25.665 51.936 ;
      RECT 0.048 52.608 25.665 52.704 ;
      RECT 0.048 53.376 25.665 53.472 ;
      RECT 0.048 54.144 25.665 54.24 ;
      RECT 0.048 54.912 25.665 55.008 ;
      RECT 0.048 55.68 25.665 55.776 ;
      RECT 0.048 56.448 25.665 56.544 ;
      RECT 0.048 57.216 25.665 57.312 ;
      RECT 0.048 57.984 25.665 58.08 ;
      RECT 0.048 58.752 25.665 58.848 ;
      RECT 0.048 59.52 25.665 59.616 ;
      RECT 0.048 60.288 25.665 60.384 ;
      RECT 0.048 61.056 25.665 61.152 ;
      RECT 0.048 61.824 25.665 61.92 ;
      RECT 0.048 62.592 25.665 62.688 ;
      RECT 0.048 63.36 25.665 63.456 ;
      RECT 0.048 64.128 25.665 64.224 ;
      RECT 0.048 64.896 25.665 64.992 ;
      RECT 0.048 65.664 25.665 65.76 ;
      RECT 0.048 66.432 25.665 66.528 ;
      RECT 0.048 67.2 25.665 67.296 ;
      RECT 0.048 67.968 25.665 68.064 ;
      RECT 0.048 68.736 25.665 68.832 ;
      RECT 0.048 69.504 25.665 69.6 ;
      RECT 0.048 70.272 25.665 70.368 ;
      RECT 0.048 71.04 25.665 71.136 ;
      RECT 0.048 71.808 25.665 71.904 ;
      RECT 0.048 72.576 25.665 72.672 ;
      RECT 0.048 73.344 25.665 73.44 ;
      RECT 0.048 74.112 25.665 74.208 ;
      RECT 0.048 74.88 25.665 74.976 ;
      RECT 0.048 75.648 25.665 75.744 ;
      RECT 0.048 76.416 25.665 76.512 ;
      RECT 0.048 77.184 25.665 77.28 ;
      RECT 0.048 77.952 25.665 78.048 ;
      RECT 0.048 78.72 25.665 78.816 ;
      RECT 0.048 79.488 25.665 79.584 ;
      RECT 0.048 80.256 25.665 80.352 ;
      RECT 0.048 81.024 25.665 81.12 ;
      RECT 0.048 81.792 25.665 81.888 ;
      RECT 0.048 82.56 25.665 82.656 ;
      RECT 0.048 83.328 25.665 83.424 ;
      RECT 0.048 84.096 25.665 84.192 ;
      RECT 0.048 84.864 25.665 84.96 ;
      RECT 0.048 85.632 25.665 85.728 ;
      RECT 0.048 86.4 25.665 86.496 ;
      RECT 0.048 87.168 25.665 87.264 ;
      RECT 0.048 87.936 25.665 88.032 ;
      RECT 0.048 88.704 25.665 88.8 ;
      RECT 0.048 89.472 25.665 89.568 ;
      RECT 0.048 90.24 25.665 90.336 ;
      RECT 0.048 91.008 25.665 91.104 ;
      RECT 0.048 91.776 25.665 91.872 ;
      RECT 0.048 92.544 25.665 92.64 ;
      RECT 0.048 93.312 25.665 93.408 ;
      RECT 0.048 94.08 25.665 94.176 ;
      RECT 0.048 94.848 25.665 94.944 ;
      RECT 0.048 95.616 25.665 95.712 ;
      RECT 0.048 96.384 25.665 96.48 ;
      RECT 0.048 97.152 25.665 97.248 ;
      RECT 0.048 97.92 25.665 98.016 ;
      RECT 0.048 98.688 25.665 98.784 ;
      RECT 0.048 99.456 25.665 99.552 ;
      RECT 0.048 100.224 25.665 100.32 ;
      RECT 0.048 100.992 25.665 101.088 ;
      RECT 0.048 101.76 25.665 101.856 ;
      RECT 0.048 102.528 25.665 102.624 ;
      RECT 0.048 103.296 25.665 103.392 ;
      RECT 0.048 104.064 25.665 104.16 ;
      RECT 0.048 104.832 25.665 104.928 ;
      RECT 0.048 105.6 25.665 105.696 ;
      RECT 0.048 106.368 25.665 106.464 ;
      RECT 0.048 107.136 25.665 107.232 ;
      RECT 0.048 107.904 25.665 108 ;
      RECT 0.048 108.672 25.665 108.768 ;
      RECT 0.048 109.44 25.665 109.536 ;
      RECT 0.048 110.208 25.665 110.304 ;
      RECT 0.048 110.976 25.665 111.072 ;
      RECT 0.048 111.744 25.665 111.84 ;
      RECT 0.048 112.512 25.665 112.608 ;
      RECT 0.048 113.28 25.665 113.376 ;
      RECT 0.048 114.048 25.665 114.144 ;
      RECT 0.048 114.816 25.665 114.912 ;
      RECT 0.048 115.584 25.665 115.68 ;
      RECT 0.048 116.352 25.665 116.448 ;
      RECT 0.048 117.12 25.665 117.216 ;
      RECT 0.048 117.888 25.665 117.984 ;
      RECT 0.048 118.656 25.665 118.752 ;
      RECT 0.048 119.424 25.665 119.52 ;
      RECT 0.048 120.192 25.665 120.288 ;
      RECT 0.048 120.96 25.665 121.056 ;
      RECT 0.048 121.728 25.665 121.824 ;
      RECT 0.048 122.496 25.665 122.592 ;
      RECT 0.048 123.264 25.665 123.36 ;
      RECT 0.048 124.032 25.665 124.128 ;
      RECT 0.048 124.8 25.665 124.896 ;
      RECT 0.048 125.568 25.665 125.664 ;
      RECT 0.048 126.336 25.665 126.432 ;
      RECT 0.048 127.104 25.665 127.2 ;
      RECT 0.048 127.872 25.665 127.968 ;
      RECT 0.048 128.64 25.665 128.736 ;
      RECT 0.048 129.408 25.665 129.504 ;
      RECT 0.048 130.176 25.665 130.272 ;
      RECT 0.048 130.944 25.665 131.04 ;
      RECT 0.048 131.712 25.665 131.808 ;
      RECT 0.048 132.48 25.665 132.576 ;
    END
  END VDD
  OBS
    LAYER M1_m ;
    RECT 0 0 25.713 132.581 ;
    LAYER M2_m ;
    RECT 0 0 25.713 132.581 ;
    LAYER M3_m ;
    RECT 0 0 25.713 132.581 ;
  END
END ht_asap7_leon3vtabus_tensorFile_0_0_ext_upper

END LIBRARY
